# PARTIAL NDA constrain

#------------------------------------------------------

VERSION 5.7 ;
BUSBITCHARS "[]" ;
DIVIDERCHAR "/" ;

UNITS
    DATABASE MICRONS 2000  ;
    CAPACITANCE PICOFARADS 1 ;
    CURRENT MILLIAMPS 1 ;
    RESISTANCE OHMS 1 ;
END UNITS

SITE PACKAGE
  SYMMETRY X Y ;
  CLASS core ;
  SIZE 0.56 BY 5.04 ;
END PACKAGE

PROPERTYDEFINITIONS
  LAYER LEF58_EOLENCLOSURE STRING ;
  LAYER LEF58_TYPE STRING ;
END PROPERTYDEFINITIONS

MANUFACTURINGGRID 0.005 ;
CLEARANCEMEASURE EUCLIDEAN ;
USEMINSPACING OBS ON ;

# LAYER Poly2
#    TYPE MASTERSLICE ;
# END Poly2

# LAYER CON
#    TYPE CUT ;
# END CON

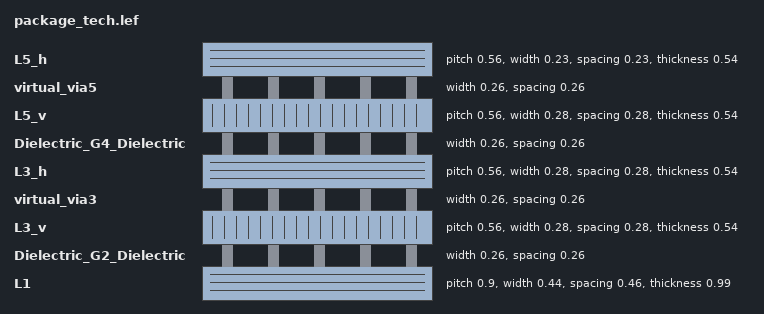
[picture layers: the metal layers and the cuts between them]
LAYER L1
    TYPE ROUTING ;
    DIRECTION HORIZONTAL ;

    OFFSET 0.0 ;  


    PITCH 0.9 ;
    MINWIDTH 0.440 ;
    WIDTH   0.440 ;                      # MT.1
    AREA    0.5625 ;                     # MT.4
    SPACING 0.460 ;                      # MT.2a
    SPACING 0.600 RANGE 10.005 999.00 ;  # MT.2b

    DCCURRENTDENSITY AVERAGE 1.21 ;
    ACCURRENTDENSITY AVERAGE 1.82 ;
    RESISTANCE RPERSQ 0.04000 ;

    THICKNESS 0.99 ;

    ANTENNAMODEL OXIDE1 ;
    ANTENNADIFFSIDEAREARATIO 400 ;
    ANTENNAGATEPLUSDIFF 2 ;

    CAPACITANCE CPERSQDIST 0.0000394 ;

    MINIMUMDENSITY 30.0 ;
    DENSITYCHECKWINDOW 200.0 200.0 ;
    DENSITYCHECKSTEP 100.0 ;

END L1

LAYER Dielectric_G2_Dielectric
  TYPE CUT ;
  SPACING 0.26 ;
  WIDTH   0.26 ;

  ENCLOSURE BELOW 0.01 0.06 ;
 # ENCLOSURE ABOVE 0.01 0.09 ;
  ENCLOSURE ABOVE 0.01 0.06 ;

  # a bit conservative for Vn.3/4a without considering the protrusion length of 0.28
  PROPERTY LEF58_EOLENCLOSURE " EOLENCLOSURE 0.34 0.06 ; " ;

  ARRAYSPACING CUTSPACING 0.36 ARRAYCUTS 4 SPACING 0.36 ; # Vn.2b

  ACCURRENTDENSITY AVERAGE 0.28 ;
  DCCURRENTDENSITY AVERAGE 0.18 ;
  ANTENNAMODEL OXIDE1 ;
  ANTENNAAREARATIO 20.0 ;
END Dielectric_G2_Dielectric

LAYER L3_v
    TYPE ROUTING ;
    DIRECTION VERTICAL ;

    PITCH 0.56 ;
    OFFSET 0.0 ;  

    MINWIDTH 0.280 ;
    WIDTH 0.280 ;                        # Mn.1  (n>1)
    SPACING 0.280 ;                      # Mn.2a (n>1)
    SPACING 0.300 RANGE 10.005 999.00 ;  # Mn.2b
    AREA 0.1444 ;                        # Mn.3

    THICKNESS 0.54 ;
    ANTENNAMODEL OXIDE1 ;
    ANTENNADIFFSIDEAREARATIO 400 ;
    ANTENNAGATEPLUSDIFF 2 ;

    DCCURRENTDENSITY AVERAGE 0.67 ;
    ACCURRENTDENSITY AVERAGE 1.00 ;

    CAPACITANCE CPERSQDIST 0.0000394 ;
    RESISTANCE RPERSQ 0.090000 ;

    MINIMUMDENSITY 30.0 ;
    DENSITYCHECKWINDOW 200.0 200.0 ;
    DENSITYCHECKSTEP 100.0 ;

END L3_v


LAYER virtual_via3
  TYPE CUT ;
  SPACING 0.26 ;
  WIDTH   0.26 ;

  ENCLOSURE BELOW 0.01 0.06 ;
  ENCLOSURE ABOVE 0.01 0.06 ;

  # a bit conservative for Vn.3/4a without considering the protrusion length of 0.28
  PROPERTY LEF58_EOLENCLOSURE " EOLENCLOSURE 0.34 0.06 ; " ;

  ARRAYSPACING CUTSPACING 0.36 ARRAYCUTS 4 SPACING 0.36 ; # Vn.2b

  ACCURRENTDENSITY AVERAGE 0.28 ;
  DCCURRENTDENSITY AVERAGE 0.18 ;
  ANTENNAMODEL OXIDE1 ;
  ANTENNAAREARATIO 20.0 ;
END virtual_via3


LAYER L3_h
    TYPE ROUTING ;
    DIRECTION HORIZONTAL ;

    PITCH 0.56 ;
    OFFSET 0.0 ;  

    MINWIDTH 0.280 ;
    WIDTH 0.280 ;                        # Mn.1  (n>1)
    SPACING 0.280 ;                      # Mn.2a (n>1)
    SPACING 0.300 RANGE 10.005 999.00 ;  # Mn.2b
    AREA 0.1444 ;                        # Mn.3

    THICKNESS 0.54 ;
    ANTENNAMODEL OXIDE1 ;
    ANTENNADIFFSIDEAREARATIO 400 ;
    ANTENNAGATEPLUSDIFF 2 ;

    DCCURRENTDENSITY AVERAGE 0.67 ;
    ACCURRENTDENSITY AVERAGE 1.00 ;

    CAPACITANCE CPERSQDIST 0.0000394 ;
    RESISTANCE RPERSQ 0.090000 ;

    MINIMUMDENSITY 30.0 ;
    DENSITYCHECKWINDOW 200.0 200.0 ;
    DENSITYCHECKSTEP 100.0 ;

END L3_h

LAYER Dielectric_G4_Dielectric
  TYPE CUT ;
  SPACING 0.26 ;
  WIDTH   0.26 ;

  ENCLOSURE BELOW 0.01 0.06 ;
  ENCLOSURE ABOVE 0.01 0.06 ;

  # a bit conservative for Vn.3/4a without considering the protrusion length of 0.28
  PROPERTY LEF58_EOLENCLOSURE " EOLENCLOSURE 0.34 0.06 ; " ;

  ARRAYSPACING CUTSPACING 0.36 ARRAYCUTS 4 SPACING 0.36 ; # Vn.2b

  ACCURRENTDENSITY AVERAGE 0.28 ;
  DCCURRENTDENSITY AVERAGE 0.18 ;
  ANTENNAMODEL OXIDE1 ;
  ANTENNAAREARATIO 20.0 ;
END Dielectric_G4_Dielectric

LAYER L5_v
    TYPE ROUTING ;
    DIRECTION VERTICAL ;

    PITCH 0.56 ;
    OFFSET 0.0 ;  

    MINWIDTH 0.280 ;
    WIDTH 0.280 ;                        # Mn.1  (n>1)
    SPACING 0.280 ;                      # Mn.2a (n>1)
    SPACING 0.300 RANGE 10.005 999.00 ;  # Mn.2b
    AREA 0.1444 ;                        # Mn.3

    THICKNESS 0.54 ;
    ANTENNAMODEL OXIDE1 ;
    ANTENNADIFFSIDEAREARATIO 400 ;
    ANTENNAGATEPLUSDIFF 2 ;

    DCCURRENTDENSITY AVERAGE 0.67 ;
    ACCURRENTDENSITY AVERAGE 1.00 ;

    CAPACITANCE CPERSQDIST 0.0000394 ;
    RESISTANCE RPERSQ 0.090000 ;

    MINIMUMDENSITY 30.0 ;
    DENSITYCHECKWINDOW 200.0 200.0 ;
    DENSITYCHECKSTEP 100.0 ;

END L5_v

LAYER virtual_via5
  TYPE CUT ;
  SPACING 0.26 ;
  WIDTH   0.26 ;

  ENCLOSURE BELOW 0.00 0.06 ;
  ENCLOSURE ABOVE 0.01 0.06 ;
  PROPERTY LEF58_EOLENCLOSURE "
  	EOLENCLOSURE 0.34 0.06 ;" ; 

  ARRAYSPACING CUTSPACING 0.36 ARRAYCUTS 4 SPACING 0.36 ; # Vn.2b

  ACCURRENTDENSITY AVERAGE 0.28 ;
  DCCURRENTDENSITY AVERAGE 0.18 ;
  ANTENNAMODEL OXIDE1 ;
  ANTENNAAREARATIO 20.0 ;
END virtual_via5

LAYER L5_h
    TYPE ROUTING ;
    DIRECTION HORIZONTAL ;

    PITCH 0.56 ;
    OFFSET 0.0 ;  

    MINWIDTH 0.230 ;                   # Mn.1  (n=1)
    WIDTH 0.230 ;                      # Mn.1  (n=1)
    SPACING 0.230  ;                   # Mn.2a (n=1)
    SPACING 0.300 RANGE 10.005 999.00 ; # Mn.2b
    AREA 0.1444 ;                      # Mn.3

    THICKNESS 0.54 ;
    ANTENNAMODEL OXIDE1 ;
    ANTENNASIDEAREARATIO 400 ;

    DCCURRENTDENSITY AVERAGE 0.67 ;
    ACCURRENTDENSITY AVERAGE 1.00 ;

    CAPACITANCE CPERSQDIST 0.0000394 ;
    RESISTANCE RPERSQ 0.090000 ;

    MINIMUMDENSITY 30.0 ;
    DENSITYCHECKWINDOW 200.0 200.0 ;
    DENSITYCHECKSTEP 100.0 ;

END L5_h



# LAYER OVERLAP
#   TYPE OVERLAP ;
# END OVERLAP

# LAYER PR_bndry
#     TYPE MASTERSLICE ;
# END PR_bndry


#------------------------------------------------------------
#  virtual_via5 VIA SECTION 
#------------------------------------------------------------
 VIA virtual_via5_HH  DEFAULT
 RESISTANCE 4.500 ;
 LAYER virtual_via5 ;
 RECT -0.130 -0.130 0.130 0.130 ;
 LAYER L5_h ;
 RECT -0.190 -0.130 0.190 0.130 ;
 LAYER L5_v ;
 RECT -0.190 -0.140 0.190 0.140 ;
 END virtual_via5_HH 
 
 VIA virtual_via5_HV  DEFAULT
 RESISTANCE 4.500 ;
 LAYER virtual_via5 ;
 RECT -0.130 -0.130 0.130 0.130 ;
 LAYER L5_h ;
 RECT -0.190 -0.130 0.190 0.130 ;
 LAYER L5_v ;
 RECT -0.140 -0.190 0.140 0.190 ;
 END virtual_via5_HV 
 
 VIA virtual_via5_VH  DEFAULT
 RESISTANCE 4.500 ;
 LAYER virtual_via5 ;
 RECT -0.130 -0.130 0.130 0.130 ;
 LAYER L5_h ;
 RECT -0.130 -0.190 0.130 0.190 ;
 LAYER L5_v ;
 RECT -0.190 -0.140 0.190 0.140 ;
 END virtual_via5_VH 
 
 VIA virtual_via5_VV  DEFAULT
 RESISTANCE 4.500 ;
 LAYER virtual_via5 ;
 RECT -0.130 -0.130 0.130 0.130 ;
 LAYER L5_h ;
 RECT -0.130 -0.190 0.130 0.190 ;
 LAYER L5_v ;
 RECT -0.140 -0.190 0.140 0.190 ;
 END virtual_via5_VV 
 
 VIA virtual_via5_2CUT_H
 LAYER virtual_via5 ;
 RECT -0.390 -0.130 -0.130 0.130 ;
 RECT 0.130 -0.130 0.390 0.130 ;
 LAYER L5_h ;
 RECT -0.450 -0.130 0.450 0.130 ;
 LAYER L5_v ;
 RECT -0.400 -0.190 0.400 0.190 ;
 END virtual_via5_2CUT_H
 
 VIA virtual_via5_2CUT_V
 LAYER virtual_via5 ;
 RECT -0.130 -0.390 0.130 -0.130 ;
 RECT -0.130 0.130 0.130 0.390 ;
 LAYER L5_h ;
 RECT -0.190 -0.390 0.190 0.390 ;
 LAYER L5_v ;
 RECT -0.140 -0.450 0.140 0.450 ;
 END virtual_via5_2CUT_V
 
 VIA virtual_via5_2X2_0_60_10_60_H_H  DEFAULT
 LAYER virtual_via5 ;
 RECT -0.390 -0.390 -0.130 -0.130 ;
 RECT 0.130 -0.390 0.390 -0.130 ;
 RECT -0.390 0.130 -0.130 0.390 ;
 RECT 0.130 0.130 0.390 0.390 ;
 LAYER L5_h ;
 RECT -0.450 -0.390 0.450 0.390 ;
 LAYER L5_v ;
 RECT -0.450 -0.400 0.450 0.400 ;
 END virtual_via5_2X2_0_60_10_60_H_H 
 
 VIA virtual_via5_2X2_0_60_10_60_H_V  DEFAULT
 LAYER virtual_via5 ;
 RECT -0.390 -0.390 -0.130 -0.130 ;
 RECT 0.130 -0.390 0.390 -0.130 ;
 RECT -0.390 0.130 -0.130 0.390 ;
 RECT 0.130 0.130 0.390 0.390 ;
 LAYER L5_h ;
 RECT -0.450 -0.390 0.450 0.390 ;
 LAYER L5_v ;
 RECT -0.400 -0.450 0.400 0.450 ;
 END virtual_via5_2X2_0_60_10_60_H_V 
 
 VIA virtual_via5_2X2_0_60_10_60_V_H  DEFAULT
 LAYER virtual_via5 ;
 RECT -0.390 -0.390 -0.130 -0.130 ;
 RECT 0.130 -0.390 0.390 -0.130 ;
 RECT -0.390 0.130 -0.130 0.390 ;
 RECT 0.130 0.130 0.390 0.390 ;
 LAYER L5_h ;
 RECT -0.390 -0.450 0.390 0.450 ;
 LAYER L5_v ;
 RECT -0.450 -0.400 0.450 0.400 ;
 END virtual_via5_2X2_0_60_10_60_V_H 
 
 VIA virtual_via5_2X2_0_60_10_60_V_V  DEFAULT
 LAYER virtual_via5 ;
 RECT -0.390 -0.390 -0.130 -0.130 ;
 RECT 0.130 -0.390 0.390 -0.130 ;
 RECT -0.390 0.130 -0.130 0.390 ;
 RECT 0.130 0.130 0.390 0.390 ;
 LAYER L5_h ;
 RECT -0.390 -0.450 0.390 0.450 ;
 LAYER L5_v ;
 RECT -0.400 -0.450 0.400 0.450 ;
 END virtual_via5_2X2_0_60_10_60_V_V 
 
VIARULE virtual_via5_GEN_HH GENERATE
  LAYER L5_h ;
    ENCLOSURE 0.060 0.000 ;
  LAYER L5_v ;
    ENCLOSURE 0.060 0.010 ;
  LAYER virtual_via5 ;
    RECT -0.130 -0.130 0.130 0.130 ;
    SPACING 0.520 BY 0.520 ;
END virtual_via5_GEN_HH

VIARULE virtual_via5_GEN_HV GENERATE
  LAYER L5_h ;
    ENCLOSURE 0.060 0.000 ;
  LAYER L5_v ;
    ENCLOSURE 0.010 0.060 ;
  LAYER virtual_via5 ;
    RECT -0.130 -0.130 0.130 0.130 ;
    SPACING 0.520 BY 0.520 ;
END virtual_via5_GEN_HV

VIARULE virtual_via5_GEN_VH GENERATE
  LAYER L5_h ;
    ENCLOSURE 0.000 0.060 ;
  LAYER L5_v ;
    ENCLOSURE 0.060 0.010 ;
  LAYER virtual_via5 ;
    RECT -0.130 -0.130 0.130 0.130 ;
    SPACING 0.520 BY 0.520 ;
END virtual_via5_GEN_VH

VIARULE virtual_via5_GEN_VV GENERATE
  LAYER L5_h ;
    ENCLOSURE 0.000 0.060 ;
  LAYER L5_v ;
    ENCLOSURE 0.010 0.060 ;
  LAYER virtual_via5 ;
    RECT -0.130 -0.130 0.130 0.130 ;
    SPACING 0.520 BY 0.520 ;
END virtual_via5_GEN_VV

 VIA virtual_via5_4X4H_HH_DEFAULT  DEFAULT
 LAYER virtual_via5 ;
 RECT -1.060 -1.060 -0.800 -0.800 ;
 RECT -0.440 -1.060 -0.180 -0.800 ;
 RECT 0.180 -1.060 0.440 -0.800 ;
 RECT 0.800 -1.060 1.060 -0.800 ;
 RECT -1.060 -0.440 -0.800 -0.180 ;
 RECT -0.440 -0.440 -0.180 -0.180 ;
 RECT 0.180 -0.440 0.440 -0.180 ;
 RECT 0.800 -0.440 1.060 -0.180 ;
 RECT -1.060 0.180 -0.800 0.440 ;
 RECT -0.440 0.180 -0.180 0.440 ;
 RECT 0.180 0.180 0.440 0.440 ;
 RECT 0.800 0.180 1.060 0.440 ;
 RECT -1.060 0.800 -0.800 1.060 ;
 RECT -0.440 0.800 -0.180 1.060 ;
 RECT 0.180 0.800 0.440 1.060 ;
 RECT 0.800 0.800 1.060 1.060 ;
 LAYER L5_h ;
 RECT -1.120 -1.060 1.120 1.060 ;
 LAYER L5_v ;
 RECT -1.120 -1.070 1.120 1.070 ;
 END virtual_via5_4X4H_HH_DEFAULT 
 
 VIA virtual_via5_4X4H_HV_DEFAULT  DEFAULT
 LAYER virtual_via5 ;
 RECT -1.060 -1.060 -0.800 -0.800 ;
 RECT -0.440 -1.060 -0.180 -0.800 ;
 RECT 0.180 -1.060 0.440 -0.800 ;
 RECT 0.800 -1.060 1.060 -0.800 ;
 RECT -1.060 -0.440 -0.800 -0.180 ;
 RECT -0.440 -0.440 -0.180 -0.180 ;
 RECT 0.180 -0.440 0.440 -0.180 ;
 RECT 0.800 -0.440 1.060 -0.180 ;
 RECT -1.060 0.180 -0.800 0.440 ;
 RECT -0.440 0.180 -0.180 0.440 ;
 RECT 0.180 0.180 0.440 0.440 ;
 RECT 0.800 0.180 1.060 0.440 ;
 RECT -1.060 0.800 -0.800 1.060 ;
 RECT -0.440 0.800 -0.180 1.060 ;
 RECT 0.180 0.800 0.440 1.060 ;
 RECT 0.800 0.800 1.060 1.060 ;
 LAYER L5_h ;
 RECT -1.120 -1.060 1.120 1.060 ;
 LAYER L5_v ;
 RECT -1.070 -1.120 1.070 1.120 ;
 END virtual_via5_4X4H_HV_DEFAULT 
 
 VIA virtual_via5_4X4H_VH_DEFAULT  DEFAULT
 LAYER virtual_via5 ;
 RECT -1.060 -1.060 -0.800 -0.800 ;
 RECT -0.440 -1.060 -0.180 -0.800 ;
 RECT 0.180 -1.060 0.440 -0.800 ;
 RECT 0.800 -1.060 1.060 -0.800 ;
 RECT -1.060 -0.440 -0.800 -0.180 ;
 RECT -0.440 -0.440 -0.180 -0.180 ;
 RECT 0.180 -0.440 0.440 -0.180 ;
 RECT 0.800 -0.440 1.060 -0.180 ;
 RECT -1.060 0.180 -0.800 0.440 ;
 RECT -0.440 0.180 -0.180 0.440 ;
 RECT 0.180 0.180 0.440 0.440 ;
 RECT 0.800 0.180 1.060 0.440 ;
 RECT -1.060 0.800 -0.800 1.060 ;
 RECT -0.440 0.800 -0.180 1.060 ;
 RECT 0.180 0.800 0.440 1.060 ;
 RECT 0.800 0.800 1.060 1.060 ;
 LAYER L5_h ;
 RECT -1.060 -1.120 1.060 1.120 ;
 LAYER L5_v ;
 RECT -1.120 -1.070 1.120 1.070 ;
 END virtual_via5_4X4H_VH_DEFAULT 
 
 VIA virtual_via5_4X4H_VV_DEFAULT  DEFAULT
 LAYER virtual_via5 ;
 RECT -1.060 -1.060 -0.800 -0.800 ;
 RECT -0.440 -1.060 -0.180 -0.800 ;
 RECT 0.180 -1.060 0.440 -0.800 ;
 RECT 0.800 -1.060 1.060 -0.800 ;
 RECT -1.060 -0.440 -0.800 -0.180 ;
 RECT -0.440 -0.440 -0.180 -0.180 ;
 RECT 0.180 -0.440 0.440 -0.180 ;
 RECT 0.800 -0.440 1.060 -0.180 ;
 RECT -1.060 0.180 -0.800 0.440 ;
 RECT -0.440 0.180 -0.180 0.440 ;
 RECT 0.180 0.180 0.440 0.440 ;
 RECT 0.800 0.180 1.060 0.440 ;
 RECT -1.060 0.800 -0.800 1.060 ;
 RECT -0.440 0.800 -0.180 1.060 ;
 RECT 0.180 0.800 0.440 1.060 ;
 RECT 0.800 0.800 1.060 1.060 ;
 LAYER L5_h ;
 RECT -1.060 -1.120 1.060 1.120 ;
 LAYER L5_v ;
 RECT -1.070 -1.120 1.070 1.120 ;
 END virtual_via5_4X4H_VV_DEFAULT 
 
#------------------------------------------------------------
#  Dielectric_G4_Dielectric VIA SECTION 
#------------------------------------------------------------
 VIA Dielectric_G4_Dielectric_HH  DEFAULT
 RESISTANCE 4.500 ;
 LAYER Dielectric_G4_Dielectric ;
 RECT -0.130 -0.130 0.130 0.130 ;
 LAYER L5_v ;
 RECT -0.190 -0.140 0.190 0.140 ;
 LAYER L3_h ;
 RECT -0.190 -0.140 0.190 0.140 ;
 END Dielectric_G4_Dielectric_HH 
 
 VIA Dielectric_G4_Dielectric_HV  DEFAULT
 RESISTANCE 4.500 ;
 LAYER Dielectric_G4_Dielectric ;
 RECT -0.130 -0.130 0.130 0.130 ;
 LAYER L5_v ;
 RECT -0.190 -0.140 0.190 0.140 ;
 LAYER L3_h ;
 RECT -0.140 -0.190 0.140 0.190 ;
 END Dielectric_G4_Dielectric_HV 
 
 VIA Dielectric_G4_Dielectric_VH  DEFAULT
 RESISTANCE 4.500 ;
 LAYER Dielectric_G4_Dielectric ;
 RECT -0.130 -0.130 0.130 0.130 ;
 LAYER L5_v ;
 RECT -0.140 -0.190 0.140 0.190 ;
 LAYER L3_h ;
 RECT -0.190 -0.140 0.190 0.140 ;
 END Dielectric_G4_Dielectric_VH 
 
 VIA Dielectric_G4_Dielectric_VV  DEFAULT
 RESISTANCE 4.500 ;
 LAYER Dielectric_G4_Dielectric ;
 RECT -0.130 -0.130 0.130 0.130 ;
 LAYER L5_v ;
 RECT -0.140 -0.190 0.140 0.190 ;
 LAYER L3_h ;
 RECT -0.140 -0.190 0.140 0.190 ;
 END Dielectric_G4_Dielectric_VV 
 
 VIA Dielectric_G4_Dielectric_2CUT_H
 LAYER Dielectric_G4_Dielectric ;
 RECT -0.390 -0.130 -0.130 0.130 ;
 RECT 0.130 -0.130 0.390 0.130 ;
 LAYER L5_v ;
 RECT -0.390 -0.190 0.390 0.190 ;
 LAYER L3_h ;
 RECT -0.450 -0.140 0.450 0.140 ;
 END Dielectric_G4_Dielectric_2CUT_H
 
 VIA Dielectric_G4_Dielectric_2CUT_V
 LAYER Dielectric_G4_Dielectric ;
 RECT -0.130 -0.390 0.130 -0.130 ;
 RECT -0.130 0.130 0.130 0.390 ;
 LAYER L5_v ;
 RECT -0.130 -0.450 0.130 0.450 ;
 LAYER L3_h ;
 RECT -0.190 -0.400 0.190 0.400 ;
 END Dielectric_G4_Dielectric_2CUT_V
 
 VIA Dielectric_G4_Dielectric_2X2_0_60_10_60_H_H  DEFAULT
 LAYER Dielectric_G4_Dielectric ;
 RECT -0.390 -0.390 -0.130 -0.130 ;
 RECT 0.130 -0.390 0.390 -0.130 ;
 RECT -0.390 0.130 -0.130 0.390 ;
 RECT 0.130 0.130 0.390 0.390 ;
 LAYER L5_v ;
 RECT -0.450 -0.390 0.450 0.390 ;
 LAYER L3_h ;
 RECT -0.450 -0.400 0.450 0.400 ;
 END Dielectric_G4_Dielectric_2X2_0_60_10_60_H_H 
 
 VIA Dielectric_G4_Dielectric_2X2_0_60_10_60_H_V  DEFAULT
 LAYER Dielectric_G4_Dielectric ;
 RECT -0.390 -0.390 -0.130 -0.130 ;
 RECT 0.130 -0.390 0.390 -0.130 ;
 RECT -0.390 0.130 -0.130 0.390 ;
 RECT 0.130 0.130 0.390 0.390 ;
 LAYER L5_v ;
 RECT -0.450 -0.390 0.450 0.390 ;
 LAYER L3_h ;
 RECT -0.400 -0.450 0.400 0.450 ;
 END Dielectric_G4_Dielectric_2X2_0_60_10_60_H_V 
 
 VIA Dielectric_G4_Dielectric_2X2_0_60_10_60_V_H  DEFAULT
 LAYER Dielectric_G4_Dielectric ;
 RECT -0.390 -0.390 -0.130 -0.130 ;
 RECT 0.130 -0.390 0.390 -0.130 ;
 RECT -0.390 0.130 -0.130 0.390 ;
 RECT 0.130 0.130 0.390 0.390 ;
 LAYER L5_v ;
 RECT -0.390 -0.450 0.390 0.450 ;
 LAYER L3_h ;
 RECT -0.450 -0.400 0.450 0.400 ;
 END Dielectric_G4_Dielectric_2X2_0_60_10_60_V_H 
 
 VIA Dielectric_G4_Dielectric_2X2_0_60_10_60_V_V  DEFAULT
 LAYER Dielectric_G4_Dielectric ;
 RECT -0.390 -0.390 -0.130 -0.130 ;
 RECT 0.130 -0.390 0.390 -0.130 ;
 RECT -0.390 0.130 -0.130 0.390 ;
 RECT 0.130 0.130 0.390 0.390 ;
 LAYER L5_v ;
 RECT -0.390 -0.450 0.390 0.450 ;
 LAYER L3_h ;
 RECT -0.400 -0.450 0.400 0.450 ;
 END Dielectric_G4_Dielectric_2X2_0_60_10_60_V_V 
 
VIARULE Dielectric_G4_Dielectric_GEN_HH GENERATE
  LAYER L5_v ;
    ENCLOSURE 0.060 0.010 ;
  LAYER L3_h ;
    ENCLOSURE 0.060 0.010 ;
  LAYER Dielectric_G4_Dielectric ;
    RECT -0.130 -0.130 0.130 0.130 ;
    SPACING 0.520 BY 0.520 ;
END Dielectric_G4_Dielectric_GEN_HH

VIARULE Dielectric_G4_Dielectric_GEN_HV GENERATE
  LAYER L5_v ;
    ENCLOSURE 0.060 0.010 ;
  LAYER L3_h ;
    ENCLOSURE 0.010 0.060 ;
  LAYER Dielectric_G4_Dielectric ;
    RECT -0.130 -0.130 0.130 0.130 ;
    SPACING 0.520 BY 0.520 ;
END Dielectric_G4_Dielectric_GEN_HV

VIARULE Dielectric_G4_Dielectric_GEN_VH GENERATE
  LAYER L5_v ;
    ENCLOSURE 0.010 0.060 ;
  LAYER L3_h ;
    ENCLOSURE 0.060 0.010 ;
  LAYER Dielectric_G4_Dielectric ;
    RECT -0.130 -0.130 0.130 0.130 ;
    SPACING 0.520 BY 0.520 ;
END Dielectric_G4_Dielectric_GEN_VH

VIARULE Dielectric_G4_Dielectric_GEN_VV GENERATE
  LAYER L5_v ;
    ENCLOSURE 0.010 0.060 ;
  LAYER L3_h ;
    ENCLOSURE 0.010 0.060 ;
  LAYER Dielectric_G4_Dielectric ;
    RECT -0.130 -0.130 0.130 0.130 ;
    SPACING 0.520 BY 0.520 ;
END Dielectric_G4_Dielectric_GEN_VV

 VIA Dielectric_G4_Dielectric_4X4H_HH_DEFAULT  DEFAULT
 LAYER Dielectric_G4_Dielectric ;
 RECT -1.060 -1.060 -0.800 -0.800 ;
 RECT -0.440 -1.060 -0.180 -0.800 ;
 RECT 0.180 -1.060 0.440 -0.800 ;
 RECT 0.800 -1.060 1.060 -0.800 ;
 RECT -1.060 -0.440 -0.800 -0.180 ;
 RECT -0.440 -0.440 -0.180 -0.180 ;
 RECT 0.180 -0.440 0.440 -0.180 ;
 RECT 0.800 -0.440 1.060 -0.180 ;
 RECT -1.060 0.180 -0.800 0.440 ;
 RECT -0.440 0.180 -0.180 0.440 ;
 RECT 0.180 0.180 0.440 0.440 ;
 RECT 0.800 0.180 1.060 0.440 ;
 RECT -1.060 0.800 -0.800 1.060 ;
 RECT -0.440 0.800 -0.180 1.060 ;
 RECT 0.180 0.800 0.440 1.060 ;
 RECT 0.800 0.800 1.060 1.060 ;
 LAYER L5_v ;
 RECT -1.120 -1.070 1.120 1.070 ;
 LAYER L3_h ;
 RECT -1.120 -1.070 1.120 1.070 ;
 END Dielectric_G4_Dielectric_4X4H_HH_DEFAULT 
 
 VIA Dielectric_G4_Dielectric_4X4H_HV_DEFAULT  DEFAULT
 LAYER Dielectric_G4_Dielectric ;
 RECT -1.060 -1.060 -0.800 -0.800 ;
 RECT -0.440 -1.060 -0.180 -0.800 ;
 RECT 0.180 -1.060 0.440 -0.800 ;
 RECT 0.800 -1.060 1.060 -0.800 ;
 RECT -1.060 -0.440 -0.800 -0.180 ;
 RECT -0.440 -0.440 -0.180 -0.180 ;
 RECT 0.180 -0.440 0.440 -0.180 ;
 RECT 0.800 -0.440 1.060 -0.180 ;
 RECT -1.060 0.180 -0.800 0.440 ;
 RECT -0.440 0.180 -0.180 0.440 ;
 RECT 0.180 0.180 0.440 0.440 ;
 RECT 0.800 0.180 1.060 0.440 ;
 RECT -1.060 0.800 -0.800 1.060 ;
 RECT -0.440 0.800 -0.180 1.060 ;
 RECT 0.180 0.800 0.440 1.060 ;
 RECT 0.800 0.800 1.060 1.060 ;
 LAYER L5_v ;
 RECT -1.120 -1.070 1.120 1.070 ;
 LAYER L3_h ;
 RECT -1.070 -1.120 1.070 1.120 ;
 END Dielectric_G4_Dielectric_4X4H_HV_DEFAULT 
 
 VIA Dielectric_G4_Dielectric_4X4H_VH_DEFAULT  DEFAULT
 LAYER Dielectric_G4_Dielectric ;
 RECT -1.060 -1.060 -0.800 -0.800 ;
 RECT -0.440 -1.060 -0.180 -0.800 ;
 RECT 0.180 -1.060 0.440 -0.800 ;
 RECT 0.800 -1.060 1.060 -0.800 ;
 RECT -1.060 -0.440 -0.800 -0.180 ;
 RECT -0.440 -0.440 -0.180 -0.180 ;
 RECT 0.180 -0.440 0.440 -0.180 ;
 RECT 0.800 -0.440 1.060 -0.180 ;
 RECT -1.060 0.180 -0.800 0.440 ;
 RECT -0.440 0.180 -0.180 0.440 ;
 RECT 0.180 0.180 0.440 0.440 ;
 RECT 0.800 0.180 1.060 0.440 ;
 RECT -1.060 0.800 -0.800 1.060 ;
 RECT -0.440 0.800 -0.180 1.060 ;
 RECT 0.180 0.800 0.440 1.060 ;
 RECT 0.800 0.800 1.060 1.060 ;
 LAYER L5_v ;
 RECT -1.070 -1.120 1.070 1.120 ;
 LAYER L3_h ;
 RECT -1.120 -1.070 1.120 1.070 ;
 END Dielectric_G4_Dielectric_4X4H_VH_DEFAULT 
 
 VIA Dielectric_G4_Dielectric_4X4H_VV_DEFAULT  DEFAULT
 LAYER Dielectric_G4_Dielectric ;
 RECT -1.060 -1.060 -0.800 -0.800 ;
 RECT -0.440 -1.060 -0.180 -0.800 ;
 RECT 0.180 -1.060 0.440 -0.800 ;
 RECT 0.800 -1.060 1.060 -0.800 ;
 RECT -1.060 -0.440 -0.800 -0.180 ;
 RECT -0.440 -0.440 -0.180 -0.180 ;
 RECT 0.180 -0.440 0.440 -0.180 ;
 RECT 0.800 -0.440 1.060 -0.180 ;
 RECT -1.060 0.180 -0.800 0.440 ;
 RECT -0.440 0.180 -0.180 0.440 ;
 RECT 0.180 0.180 0.440 0.440 ;
 RECT 0.800 0.180 1.060 0.440 ;
 RECT -1.060 0.800 -0.800 1.060 ;
 RECT -0.440 0.800 -0.180 1.060 ;
 RECT 0.180 0.800 0.440 1.060 ;
 RECT 0.800 0.800 1.060 1.060 ;
 LAYER L5_v ;
 RECT -1.070 -1.120 1.070 1.120 ;
 LAYER L3_h ;
 RECT -1.070 -1.120 1.070 1.120 ;
 END Dielectric_G4_Dielectric_4X4H_VV_DEFAULT 
 
#------------------------------------------------------------
#  virtual_via3 VIA SECTION 
#------------------------------------------------------------
 VIA virtual_via3_HH  DEFAULT
 RESISTANCE 4.500 ;
 LAYER virtual_via3 ;
 RECT -0.130 -0.130 0.130 0.130 ;
 LAYER L3_h ;
 RECT -0.190 -0.140 0.190 0.140 ;
 LAYER L3_v ;
 RECT -0.190 -0.140 0.190 0.140 ;
 END virtual_via3_HH 
 
 VIA virtual_via3_HV  DEFAULT
 RESISTANCE 4.500 ;
 LAYER virtual_via3 ;
 RECT -0.130 -0.130 0.130 0.130 ;
 LAYER L3_h ;
 RECT -0.190 -0.140 0.190 0.140 ;
 LAYER L3_v ;
 RECT -0.140 -0.190 0.140 0.190 ;
 END virtual_via3_HV 
 
 VIA virtual_via3_VH  DEFAULT
 RESISTANCE 4.500 ;
 LAYER virtual_via3 ;
 RECT -0.130 -0.130 0.130 0.130 ;
 LAYER L3_h ;
 RECT -0.140 -0.190 0.140 0.190 ;
 LAYER L3_v ;
 RECT -0.190 -0.140 0.190 0.140 ;
 END virtual_via3_VH 
 
 VIA virtual_via3_VV  DEFAULT
 RESISTANCE 4.500 ;
 LAYER virtual_via3 ;
 RECT -0.130 -0.130 0.130 0.130 ;
 LAYER L3_h ;
 RECT -0.140 -0.190 0.140 0.190 ;
 LAYER L3_v ;
 RECT -0.140 -0.190 0.140 0.190 ;
 END virtual_via3_VV 
 
 VIA virtual_via3_2CUT_H
 LAYER virtual_via3 ;
 RECT -0.390 -0.130 -0.130 0.130 ;
 RECT 0.130 -0.130 0.390 0.130 ;
 LAYER L3_h ;
 RECT -0.450 -0.130 0.450 0.130 ;
 LAYER L3_v ;
 RECT -0.400 -0.190 0.400 0.190 ;
 END virtual_via3_2CUT_H
 
 VIA virtual_via3_2CUT_V
 LAYER virtual_via3 ;
 RECT -0.130 -0.390 0.130 -0.130 ;
 RECT -0.130 0.130 0.130 0.390 ;
 LAYER L3_h ;
 RECT -0.190 -0.390 0.190 0.390 ;
 LAYER L3_v ;
 RECT -0.140 -0.450 0.140 0.450 ;
 END virtual_via3_2CUT_V
 
 VIA virtual_via3_2X2_0_60_10_60_H_H  DEFAULT
 LAYER virtual_via3 ;
 RECT -0.390 -0.390 -0.130 -0.130 ;
 RECT 0.130 -0.390 0.390 -0.130 ;
 RECT -0.390 0.130 -0.130 0.390 ;
 RECT 0.130 0.130 0.390 0.390 ;
 LAYER L3_h ;
 RECT -0.450 -0.390 0.450 0.390 ;
 LAYER L3_v ;
 RECT -0.450 -0.400 0.450 0.400 ;
 END virtual_via3_2X2_0_60_10_60_H_H 
 
 VIA virtual_via3_2X2_0_60_10_60_H_V  DEFAULT
 LAYER virtual_via3 ;
 RECT -0.390 -0.390 -0.130 -0.130 ;
 RECT 0.130 -0.390 0.390 -0.130 ;
 RECT -0.390 0.130 -0.130 0.390 ;
 RECT 0.130 0.130 0.390 0.390 ;
 LAYER L3_h ;
 RECT -0.450 -0.390 0.450 0.390 ;
 LAYER L3_v ;
 RECT -0.400 -0.450 0.400 0.450 ;
 END virtual_via3_2X2_0_60_10_60_H_V 
 
 VIA virtual_via3_2X2_0_60_10_60_V_H  DEFAULT
 LAYER virtual_via3 ;
 RECT -0.390 -0.390 -0.130 -0.130 ;
 RECT 0.130 -0.390 0.390 -0.130 ;
 RECT -0.390 0.130 -0.130 0.390 ;
 RECT 0.130 0.130 0.390 0.390 ;
 LAYER L3_h ;
 RECT -0.390 -0.450 0.390 0.450 ;
 LAYER L3_v ;
 RECT -0.450 -0.400 0.450 0.400 ;
 END virtual_via3_2X2_0_60_10_60_V_H 
 
 VIA virtual_via3_2X2_0_60_10_60_V_V  DEFAULT
 LAYER virtual_via3 ;
 RECT -0.390 -0.390 -0.130 -0.130 ;
 RECT 0.130 -0.390 0.390 -0.130 ;
 RECT -0.390 0.130 -0.130 0.390 ;
 RECT 0.130 0.130 0.390 0.390 ;
 LAYER L3_h ;
 RECT -0.390 -0.450 0.390 0.450 ;
 LAYER L3_v ;
 RECT -0.400 -0.450 0.400 0.450 ;
 END virtual_via3_2X2_0_60_10_60_V_V 
 
VIARULE virtual_via3_GEN_HH GENERATE
  LAYER L3_h ;
    ENCLOSURE 0.060 0.010 ;
  LAYER L3_v ;
    ENCLOSURE 0.060 0.010 ;
  LAYER virtual_via3 ;
    RECT -0.130 -0.130 0.130 0.130 ;
    SPACING 0.520 BY 0.520 ;
END virtual_via3_GEN_HH

VIARULE virtual_via3_GEN_HV GENERATE
  LAYER L3_h ;
    ENCLOSURE 0.060 0.010 ;
  LAYER L3_v ;
    ENCLOSURE 0.010 0.060 ;
  LAYER virtual_via3 ;
    RECT -0.130 -0.130 0.130 0.130 ;
    SPACING 0.520 BY 0.520 ;
END virtual_via3_GEN_HV

VIARULE virtual_via3_GEN_VH GENERATE
  LAYER L3_h ;
    ENCLOSURE 0.010 0.060 ;
  LAYER L3_v ;
    ENCLOSURE 0.060 0.010 ;
  LAYER virtual_via3 ;
    RECT -0.130 -0.130 0.130 0.130 ;
    SPACING 0.520 BY 0.520 ;
END virtual_via3_GEN_VH

VIARULE virtual_via3_GEN_VV GENERATE
  LAYER L3_h ;
    ENCLOSURE 0.010 0.060 ;
  LAYER L3_v ;
    ENCLOSURE 0.010 0.060 ;
  LAYER virtual_via3 ;
    RECT -0.130 -0.130 0.130 0.130 ;
    SPACING 0.520 BY 0.520 ;
END virtual_via3_GEN_VV

 VIA virtual_via3_4X4H_HH_DEFAULT  DEFAULT
 LAYER virtual_via3 ;
 RECT -1.060 -1.060 -0.800 -0.800 ;
 RECT -0.440 -1.060 -0.180 -0.800 ;
 RECT 0.180 -1.060 0.440 -0.800 ;
 RECT 0.800 -1.060 1.060 -0.800 ;
 RECT -1.060 -0.440 -0.800 -0.180 ;
 RECT -0.440 -0.440 -0.180 -0.180 ;
 RECT 0.180 -0.440 0.440 -0.180 ;
 RECT 0.800 -0.440 1.060 -0.180 ;
 RECT -1.060 0.180 -0.800 0.440 ;
 RECT -0.440 0.180 -0.180 0.440 ;
 RECT 0.180 0.180 0.440 0.440 ;
 RECT 0.800 0.180 1.060 0.440 ;
 RECT -1.060 0.800 -0.800 1.060 ;
 RECT -0.440 0.800 -0.180 1.060 ;
 RECT 0.180 0.800 0.440 1.060 ;
 RECT 0.800 0.800 1.060 1.060 ;
 LAYER L3_h ;
 RECT -1.120 -1.070 1.120 1.070 ;
 LAYER L3_v ;
 RECT -1.120 -1.070 1.120 1.070 ;
 END virtual_via3_4X4H_HH_DEFAULT 
 
 VIA virtual_via3_4X4H_HV_DEFAULT  DEFAULT
 LAYER virtual_via3 ;
 RECT -1.060 -1.060 -0.800 -0.800 ;
 RECT -0.440 -1.060 -0.180 -0.800 ;
 RECT 0.180 -1.060 0.440 -0.800 ;
 RECT 0.800 -1.060 1.060 -0.800 ;
 RECT -1.060 -0.440 -0.800 -0.180 ;
 RECT -0.440 -0.440 -0.180 -0.180 ;
 RECT 0.180 -0.440 0.440 -0.180 ;
 RECT 0.800 -0.440 1.060 -0.180 ;
 RECT -1.060 0.180 -0.800 0.440 ;
 RECT -0.440 0.180 -0.180 0.440 ;
 RECT 0.180 0.180 0.440 0.440 ;
 RECT 0.800 0.180 1.060 0.440 ;
 RECT -1.060 0.800 -0.800 1.060 ;
 RECT -0.440 0.800 -0.180 1.060 ;
 RECT 0.180 0.800 0.440 1.060 ;
 RECT 0.800 0.800 1.060 1.060 ;
 LAYER L3_h ;
 RECT -1.120 -1.070 1.120 1.070 ;
 LAYER L3_v ;
 RECT -1.070 -1.120 1.070 1.120 ;
 END virtual_via3_4X4H_HV_DEFAULT 
 
 VIA virtual_via3_4X4H_VH_DEFAULT  DEFAULT
 LAYER virtual_via3 ;
 RECT -1.060 -1.060 -0.800 -0.800 ;
 RECT -0.440 -1.060 -0.180 -0.800 ;
 RECT 0.180 -1.060 0.440 -0.800 ;
 RECT 0.800 -1.060 1.060 -0.800 ;
 RECT -1.060 -0.440 -0.800 -0.180 ;
 RECT -0.440 -0.440 -0.180 -0.180 ;
 RECT 0.180 -0.440 0.440 -0.180 ;
 RECT 0.800 -0.440 1.060 -0.180 ;
 RECT -1.060 0.180 -0.800 0.440 ;
 RECT -0.440 0.180 -0.180 0.440 ;
 RECT 0.180 0.180 0.440 0.440 ;
 RECT 0.800 0.180 1.060 0.440 ;
 RECT -1.060 0.800 -0.800 1.060 ;
 RECT -0.440 0.800 -0.180 1.060 ;
 RECT 0.180 0.800 0.440 1.060 ;
 RECT 0.800 0.800 1.060 1.060 ;
 LAYER L3_h ;
 RECT -1.070 -1.120 1.070 1.120 ;
 LAYER L3_v ;
 RECT -1.120 -1.070 1.120 1.070 ;
 END virtual_via3_4X4H_VH_DEFAULT 
 
 VIA virtual_via3_4X4H_VV_DEFAULT  DEFAULT
 LAYER virtual_via3 ;
 RECT -1.060 -1.060 -0.800 -0.800 ;
 RECT -0.440 -1.060 -0.180 -0.800 ;
 RECT 0.180 -1.060 0.440 -0.800 ;
 RECT 0.800 -1.060 1.060 -0.800 ;
 RECT -1.060 -0.440 -0.800 -0.180 ;
 RECT -0.440 -0.440 -0.180 -0.180 ;
 RECT 0.180 -0.440 0.440 -0.180 ;
 RECT 0.800 -0.440 1.060 -0.180 ;
 RECT -1.060 0.180 -0.800 0.440 ;
 RECT -0.440 0.180 -0.180 0.440 ;
 RECT 0.180 0.180 0.440 0.440 ;
 RECT 0.800 0.180 1.060 0.440 ;
 RECT -1.060 0.800 -0.800 1.060 ;
 RECT -0.440 0.800 -0.180 1.060 ;
 RECT 0.180 0.800 0.440 1.060 ;
 RECT 0.800 0.800 1.060 1.060 ;
 LAYER L3_h ;
 RECT -1.070 -1.120 1.070 1.120 ;
 LAYER L3_v ;
 RECT -1.070 -1.120 1.070 1.120 ;
 END virtual_via3_4X4H_VV_DEFAULT 
 
#------------------------------------------------------------
#  Dielectric_G2_Dielectric VIA SECTION 
#------------------------------------------------------------
 VIA Dielectric_G2_Dielectric_HH  DEFAULT
 RESISTANCE 4.500 ;
 LAYER Dielectric_G2_Dielectric ;
 RECT -0.130 -0.130 0.130 0.130 ;
 LAYER L3_v ;
 RECT -0.190 -0.140 0.190 0.140 ;
 LAYER L1 ;
 RECT -0.220 -0.140 0.220 0.140 ;
 END Dielectric_G2_Dielectric_HH 
 
 VIA Dielectric_G2_Dielectric_HV  DEFAULT
 RESISTANCE 4.500 ;
 LAYER Dielectric_G2_Dielectric ;
 RECT -0.130 -0.130 0.130 0.130 ;
 LAYER L3_v ;
 RECT -0.190 -0.140 0.190 0.140 ;
 LAYER L1 ;
 RECT -0.140 -0.220 0.140 0.220 ;
 END Dielectric_G2_Dielectric_HV 
 
 VIA Dielectric_G2_Dielectric_VH  DEFAULT
 RESISTANCE 4.500 ;
 LAYER Dielectric_G2_Dielectric ;
 RECT -0.130 -0.130 0.130 0.130 ;
 LAYER L3_v ;
 RECT -0.140 -0.190 0.140 0.190 ;
 LAYER L1 ;
 RECT -0.220 -0.140 0.220 0.140 ;
 END Dielectric_G2_Dielectric_VH 
 
 VIA Dielectric_G2_Dielectric_VV  DEFAULT
 RESISTANCE 4.500 ;
 LAYER Dielectric_G2_Dielectric ;
 RECT -0.130 -0.130 0.130 0.130 ;
 LAYER L3_v ;
 RECT -0.140 -0.190 0.140 0.190 ;
 LAYER L1 ;
 RECT -0.140 -0.220 0.140 0.220 ;
 END Dielectric_G2_Dielectric_VV 
 
 VIA Dielectric_G2_Dielectric_1_HH  DEFAULT
 RESISTANCE 4.500 ;
 LAYER Dielectric_G2_Dielectric ;
 RECT -0.130 -0.130 0.130 0.130 ;
 LAYER L3_v ;
 RECT -0.190 -0.140 0.190 0.140 ;
 LAYER L1 ;
 RECT -0.190 -0.140 0.190 0.140 ;
 END Dielectric_G2_Dielectric_1_HH 
 
 VIA Dielectric_G2_Dielectric_1_HV  DEFAULT
 RESISTANCE 4.500 ;
 LAYER Dielectric_G2_Dielectric ;
 RECT -0.130 -0.130 0.130 0.130 ;
 LAYER L3_v ;
 RECT -0.190 -0.140 0.190 0.140 ;
 LAYER L1 ;
 RECT -0.140 -0.190 0.140 0.190 ;
 END Dielectric_G2_Dielectric_1_HV 
 
 VIA Dielectric_G2_Dielectric_1_VH  DEFAULT
 RESISTANCE 4.500 ;
 LAYER Dielectric_G2_Dielectric ;
 RECT -0.130 -0.130 0.130 0.130 ;
 LAYER L3_v ;
 RECT -0.140 -0.190 0.140 0.190 ;
 LAYER L1 ;
 RECT -0.190 -0.140 0.190 0.140 ;
 END Dielectric_G2_Dielectric_1_VH 
 
 VIA Dielectric_G2_Dielectric_1_VV  DEFAULT
 RESISTANCE 4.500 ;
 LAYER Dielectric_G2_Dielectric ;
 RECT -0.130 -0.130 0.130 0.130 ;
 LAYER L3_v ;
 RECT -0.140 -0.190 0.140 0.190 ;
 LAYER L1 ;
 RECT -0.140 -0.190 0.140 0.190 ;
 END Dielectric_G2_Dielectric_1_VV 
 
 VIA Dielectric_G2_Dielectric_2CUT_H
 LAYER Dielectric_G2_Dielectric ;
 RECT -0.390 -0.130 -0.130 0.130 ;
 RECT 0.130 -0.130 0.390 0.130 ;
 LAYER L3_v ;
 RECT -0.400 -0.190 0.400 0.190 ;
 LAYER L1 ;
 RECT -0.450 -0.140 0.450 0.140 ;
 END Dielectric_G2_Dielectric_2CUT_H
 
 VIA Dielectric_G2_Dielectric_2CUT_V
 LAYER Dielectric_G2_Dielectric ;
 RECT -0.130 -0.390 0.130 -0.130 ;
 RECT -0.130 0.130 0.130 0.390 ;
 LAYER L3_v ;
 RECT -0.140 -0.450 0.140 0.450 ;
 LAYER L1 ;
 RECT -0.190 -0.400 0.190 0.400 ;
 END Dielectric_G2_Dielectric_2CUT_V
 
 VIA Dielectric_G2_Dielectric_2X2_10_60_10_60_H_H  DEFAULT
 LAYER Dielectric_G2_Dielectric ;
 RECT -0.390 -0.390 -0.130 -0.130 ;
 RECT 0.130 -0.390 0.390 -0.130 ;
 RECT -0.390 0.130 -0.130 0.390 ;
 RECT 0.130 0.130 0.390 0.390 ;
 LAYER L3_v ;
 RECT -0.450 -0.400 0.450 0.400 ;
 LAYER L1 ;
 RECT -0.450 -0.400 0.450 0.400 ;
 END Dielectric_G2_Dielectric_2X2_10_60_10_60_H_H 
 
 VIA Dielectric_G2_Dielectric_2X2_10_60_10_60_H_V  DEFAULT
 LAYER Dielectric_G2_Dielectric ;
 RECT -0.390 -0.390 -0.130 -0.130 ;
 RECT 0.130 -0.390 0.390 -0.130 ;
 RECT -0.390 0.130 -0.130 0.390 ;
 RECT 0.130 0.130 0.390 0.390 ;
 LAYER L3_v ;
 RECT -0.450 -0.400 0.450 0.400 ;
 LAYER L1 ;
 RECT -0.400 -0.450 0.400 0.450 ;
 END Dielectric_G2_Dielectric_2X2_10_60_10_60_H_V 
 
 VIA Dielectric_G2_Dielectric_2X2_10_60_10_60_V_H  DEFAULT
 LAYER Dielectric_G2_Dielectric ;
 RECT -0.390 -0.390 -0.130 -0.130 ;
 RECT 0.130 -0.390 0.390 -0.130 ;
 RECT -0.390 0.130 -0.130 0.390 ;
 RECT 0.130 0.130 0.390 0.390 ;
 LAYER L3_v ;
 RECT -0.400 -0.450 0.400 0.450 ;
 LAYER L1 ;
 RECT -0.450 -0.400 0.450 0.400 ;
 END Dielectric_G2_Dielectric_2X2_10_60_10_60_V_H 
 
 VIA Dielectric_G2_Dielectric_2X2_10_60_10_60_V_V  DEFAULT
 LAYER Dielectric_G2_Dielectric ;
 RECT -0.390 -0.390 -0.130 -0.130 ;
 RECT 0.130 -0.390 0.390 -0.130 ;
 RECT -0.390 0.130 -0.130 0.390 ;
 RECT 0.130 0.130 0.390 0.390 ;
 LAYER L3_v ;
 RECT -0.400 -0.450 0.400 0.450 ;
 LAYER L1 ;
 RECT -0.400 -0.450 0.400 0.450 ;
 END Dielectric_G2_Dielectric_2X2_10_60_10_60_V_V 
 
VIARULE Dielectric_G2_Dielectric_GEN_HH GENERATE
  LAYER L3_v ;
    ENCLOSURE 0.060 0.010 ;
  LAYER L1 ;
    ENCLOSURE 0.090 0.010 ;
  LAYER Dielectric_G2_Dielectric ;
    RECT -0.130 -0.130 0.130 0.130 ;
    SPACING 0.520 BY 0.520 ;
END Dielectric_G2_Dielectric_GEN_HH

VIARULE Dielectric_G2_Dielectric_GEN_HV GENERATE
  LAYER L3_v ;
    ENCLOSURE 0.060 0.010 ;
  LAYER L1 ;
    ENCLOSURE 0.010 0.090 ;
  LAYER Dielectric_G2_Dielectric ;
    RECT -0.130 -0.130 0.130 0.130 ;
    SPACING 0.520 BY 0.520 ;
END Dielectric_G2_Dielectric_GEN_HV

VIARULE Dielectric_G2_Dielectric_GEN_VH GENERATE
  LAYER L3_v ;
    ENCLOSURE 0.010 0.060 ;
  LAYER L1 ;
    ENCLOSURE 0.090 0.010 ;
  LAYER Dielectric_G2_Dielectric ;
    RECT -0.130 -0.130 0.130 0.130 ;
    SPACING 0.520 BY 0.520 ;
END Dielectric_G2_Dielectric_GEN_VH

VIARULE Dielectric_G2_Dielectric_GEN_VV GENERATE
  LAYER L3_v ;
    ENCLOSURE 0.010 0.060 ;
  LAYER L1 ;
    ENCLOSURE 0.010 0.090 ;
  LAYER Dielectric_G2_Dielectric ;
    RECT -0.130 -0.130 0.130 0.130 ;
    SPACING 0.520 BY 0.520 ;
END Dielectric_G2_Dielectric_GEN_VV

VIARULE Dielectric_G2_Dielectric_0_RULE GENERATE
  LAYER L3_v ;
    ENCLOSURE 0.010 0.060 ;
  LAYER L1 ;
    ENCLOSURE 0.060 0.010 ;
  LAYER Dielectric_G2_Dielectric ;
    RECT -0.130 -0.130 0.130 0.130 ;
    SPACING 0.520 BY 0.520 ;
END Dielectric_G2_Dielectric_0_RULE

VIARULE Dielectric_G2_Dielectric_0 GENERATE
  LAYER L3_v ;
    ENCLOSURE 0.010 0.060 ;
  LAYER L1 ;
    ENCLOSURE 0.010 0.060 ;
  LAYER Dielectric_G2_Dielectric ;
    RECT -0.130 -0.130 0.130 0.130 ;
    SPACING 0.520 BY 0.520 ;
END Dielectric_G2_Dielectric_0

 VIA Dielectric_G2_Dielectric_4X4H_HH_DEFAULT  DEFAULT
 LAYER Dielectric_G2_Dielectric ;
 RECT -1.060 -1.060 -0.800 -0.800 ;
 RECT -0.440 -1.060 -0.180 -0.800 ;
 RECT 0.180 -1.060 0.440 -0.800 ;
 RECT 0.800 -1.060 1.060 -0.800 ;
 RECT -1.060 -0.440 -0.800 -0.180 ;
 RECT -0.440 -0.440 -0.180 -0.180 ;
 RECT 0.180 -0.440 0.440 -0.180 ;
 RECT 0.800 -0.440 1.060 -0.180 ;
 RECT -1.060 0.180 -0.800 0.440 ;
 RECT -0.440 0.180 -0.180 0.440 ;
 RECT 0.180 0.180 0.440 0.440 ;
 RECT 0.800 0.180 1.060 0.440 ;
 RECT -1.060 0.800 -0.800 1.060 ;
 RECT -0.440 0.800 -0.180 1.060 ;
 RECT 0.180 0.800 0.440 1.060 ;
 RECT 0.800 0.800 1.060 1.060 ;
 LAYER L3_v ;
 RECT -1.120 -1.070 1.120 1.070 ;
 LAYER L1 ;
 RECT -1.120 -1.070 1.120 1.070 ;
 END Dielectric_G2_Dielectric_4X4H_HH_DEFAULT 
 
 VIA Dielectric_G2_Dielectric_4X4H_HV_DEFAULT  DEFAULT
 LAYER Dielectric_G2_Dielectric ;
 RECT -1.060 -1.060 -0.800 -0.800 ;
 RECT -0.440 -1.060 -0.180 -0.800 ;
 RECT 0.180 -1.060 0.440 -0.800 ;
 RECT 0.800 -1.060 1.060 -0.800 ;
 RECT -1.060 -0.440 -0.800 -0.180 ;
 RECT -0.440 -0.440 -0.180 -0.180 ;
 RECT 0.180 -0.440 0.440 -0.180 ;
 RECT 0.800 -0.440 1.060 -0.180 ;
 RECT -1.060 0.180 -0.800 0.440 ;
 RECT -0.440 0.180 -0.180 0.440 ;
 RECT 0.180 0.180 0.440 0.440 ;
 RECT 0.800 0.180 1.060 0.440 ;
 RECT -1.060 0.800 -0.800 1.060 ;
 RECT -0.440 0.800 -0.180 1.060 ;
 RECT 0.180 0.800 0.440 1.060 ;
 RECT 0.800 0.800 1.060 1.060 ;
 LAYER L3_v ;
 RECT -1.120 -1.070 1.120 1.070 ;
 LAYER L1 ;
 RECT -1.070 -1.120 1.070 1.120 ;
 END Dielectric_G2_Dielectric_4X4H_HV_DEFAULT 
 
 VIA Dielectric_G2_Dielectric_4X4H_VH_DEFAULT  DEFAULT
 LAYER Dielectric_G2_Dielectric ;
 RECT -1.060 -1.060 -0.800 -0.800 ;
 RECT -0.440 -1.060 -0.180 -0.800 ;
 RECT 0.180 -1.060 0.440 -0.800 ;
 RECT 0.800 -1.060 1.060 -0.800 ;
 RECT -1.060 -0.440 -0.800 -0.180 ;
 RECT -0.440 -0.440 -0.180 -0.180 ;
 RECT 0.180 -0.440 0.440 -0.180 ;
 RECT 0.800 -0.440 1.060 -0.180 ;
 RECT -1.060 0.180 -0.800 0.440 ;
 RECT -0.440 0.180 -0.180 0.440 ;
 RECT 0.180 0.180 0.440 0.440 ;
 RECT 0.800 0.180 1.060 0.440 ;
 RECT -1.060 0.800 -0.800 1.060 ;
 RECT -0.440 0.800 -0.180 1.060 ;
 RECT 0.180 0.800 0.440 1.060 ;
 RECT 0.800 0.800 1.060 1.060 ;
 LAYER L3_v ;
 RECT -1.070 -1.120 1.070 1.120 ;
 LAYER L1 ;
 RECT -1.120 -1.070 1.120 1.070 ;
 END Dielectric_G2_Dielectric_4X4H_VH_DEFAULT 
 
 VIA Dielectric_G2_Dielectric_4X4H_VV_DEFAULT  DEFAULT
 LAYER Dielectric_G2_Dielectric ;
 RECT -1.060 -1.060 -0.800 -0.800 ;
 RECT -0.440 -1.060 -0.180 -0.800 ;
 RECT 0.180 -1.060 0.440 -0.800 ;
 RECT 0.800 -1.060 1.060 -0.800 ;
 RECT -1.060 -0.440 -0.800 -0.180 ;
 RECT -0.440 -0.440 -0.180 -0.180 ;
 RECT 0.180 -0.440 0.440 -0.180 ;
 RECT 0.800 -0.440 1.060 -0.180 ;
 RECT -1.060 0.180 -0.800 0.440 ;
 RECT -0.440 0.180 -0.180 0.440 ;
 RECT 0.180 0.180 0.440 0.440 ;
 RECT 0.800 0.180 1.060 0.440 ;
 RECT -1.060 0.800 -0.800 1.060 ;
 RECT -0.440 0.800 -0.180 1.060 ;
 RECT 0.180 0.800 0.440 1.060 ;
 RECT 0.800 0.800 1.060 1.060 ;
 LAYER L3_v ;
 RECT -1.070 -1.120 1.070 1.120 ;
 LAYER L1 ;
 RECT -1.070 -1.120 1.070 1.120 ;
 END Dielectric_G2_Dielectric_4X4H_VV_DEFAULT 
 

END LIBRARY
